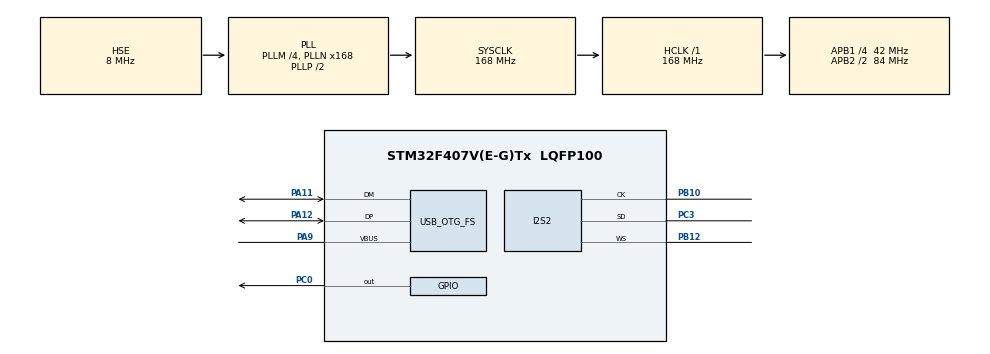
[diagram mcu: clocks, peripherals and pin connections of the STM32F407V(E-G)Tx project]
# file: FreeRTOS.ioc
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Dma.Request0=SPI2_RX
Dma.SPI2_RX.0.Direction=DMA_PERIPH_TO_MEMORY
Dma.SPI2_RX.0.FIFOMode=DMA_FIFOMODE_DISABLE
Dma.SPI2_RX.0.Instance=DMA1_Stream3
Dma.SPI2_RX.0.MemDataAlignment=DMA_MDATAALIGN_HALFWORD
Dma.SPI2_RX.0.MemInc=DMA_MINC_ENABLE
Dma.SPI2_RX.0.Mode=DMA_CIRCULAR
Dma.SPI2_RX.0.PeriphDataAlignment=DMA_PDATAALIGN_HALFWORD
Dma.SPI2_RX.0.PeriphInc=DMA_PINC_DISABLE
Dma.SPI2_RX.0.Priority=DMA_PRIORITY_LOW
FREERTOS.HEAP_NUMBER=5
FREERTOS.Tasks01=defaultTask,24,1024,StartDefaultTask,Default,NULL,Dynamic,NULL,NULL
FREERTOS.configCHECK_FOR_STACK_OVERFLOW=1
FREERTOS.configMINIMAL_STACK_SIZE=1024
FREERTOS.configTOTAL_HEAP_SIZE=30000
FREERTOS.configUSE_MALLOC_FAILED_HOOK=1
I2S2.AudioFreq=I2S_AUDIOFREQ_16K
I2S2.CPOL=I2S_CPOL_HIGH
I2S2.ErrorAudioFreq=-0.79 %
I2S2.FullDuplexMode=I2S_FULLDUPLEXMODE_DISABLE
I2S2.Instance=SPI$Index
I2S2.Mode=I2S_MODE_MASTER_RX
I2S2.RealAudioFreq=15.873 KHz
I2S2.Standard=I2S_STANDARD_LSB
I2S2.VirtualMode=I2S_MODE_MASTER
Mcu.Family=STM32F4
Mcu.Name=STM32F407V(E-G)Tx
Mcu.Package=LQFP100
NVIC.DMA1_Stream3_IRQn=true\:5\:0\:false\:false\:true\:true\:false\:true
NVIC.OTG_FS_IRQn=true\:5\:0\:false\:false\:true\:true\:false\:true
NVIC.PriorityGroup=NVIC_PRIORITYGROUP_4
NVIC.TIM1_UP_TIM10_IRQn=true\:0\:0\:false\:false\:true\:false\:false\:true
NVIC.TimeBase=TIM1_UP_TIM10_IRQn
NVIC.TimeBaseIP=TIM1
PA11.Mode=Host_Only
PA11.Signal=USB_OTG_FS_DM
PA12.Mode=Host_Only
PA12.Signal=USB_OTG_FS_DP
PA9.Mode=Activate_VBUS
PA9.Signal=USB_OTG_FS_VBUS
PB10.Mode=Half_Duplex_Master
PB10.Signal=I2S2_CK
PB12.Mode=Half_Duplex_Master
PB12.Signal=I2S2_WS
PC0.Signal=GPIO_Output
PC3.Mode=Half_Duplex_Master
PC3.Signal=I2S2_SD
PH0-OSC_IN.Mode=HSE-External-Oscillator
PH0-OSC_IN.Signal=RCC_OSC_IN
PH1-OSC_OUT.Mode=HSE-External-Oscillator
PH1-OSC_OUT.Signal=RCC_OSC_OUT
ProjectManager.HeapSize=0x200
ProjectManager.StackSize=0x400
ProjectManager.TargetToolchain=STM32CubeIDE
RCC.48MHZClocksFreq_Value=48000000
RCC.AHBFreq_Value=168000000
RCC.APB1CLKDivider=RCC_HCLK_DIV4
RCC.APB1Freq_Value=42000000
RCC.APB1TimFreq_Value=84000000
RCC.APB2CLKDivider=RCC_HCLK_DIV2
RCC.APB2Freq_Value=84000000
RCC.APB2TimFreq_Value=168000000
RCC.CortexFreq_Value=168000000
RCC.HCLKFreq_Value=168000000
RCC.HSE_VALUE=8000000
RCC.HSI_VALUE=16000000
RCC.LSE_VALUE=32768
RCC.PLLI2SN=96
RCC.PLLI2SR=6
RCC.PLLM=4
RCC.PLLN=168
RCC.PLLQ=7
RCC.SYSCLKFreq_VALUE=168000000
RCC.SYSCLKSource=RCC_SYSCLKSOURCE_PLLCLK
RCC.VCOOutputFreq_Value=336000000
USB_HOST.BSP.number=1
USB_HOST.USBH_HandleTypeDef-MSC_FS=hUsbHostFS
USB_HOST.VirtualModeFS=Msc
USB_HOST0.BSP.STBoard=false
USB_HOST0.BSP.api=Unknown
USB_HOST0.BSP.i2caddr=0
USB_HOST0.BSP.instance=PC0
USB_HOST0.BSP.ip=GPIO
USB_HOST0.BSP.mode=Output
USB_HOST0.BSP.name=Drive_VBUS_FS
USB_HOST0.BSP.solution=PC0
USB_OTG_FS.VirtualMode=Host_Only
USB_OTG_FS.phy_itface=HCD_PHY_EMBEDDED
VP_FATFS_VS_USB.Mode=USB
VP_FREERTOS_VS_CMSIS_V2.Mode=CMSIS_V2
VP_SYS_VS_tim1.Mode=TIM1
VP_USB_HOST_VS_USB_HOST_MSC_FS.Mode=MSC_FS
board=STM32F4DISCOVERY

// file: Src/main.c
/* USER CODE BEGIN Header */
/**
  ******************************************************************************
  * @file           : main.c
  * @brief          : Main program body
  ******************************************************************************
  * @attention
  *
  * <h2><center>&copy; Copyright (c) 2019 STMicroelectronics.
  * All rights reserved.</center></h2>
  *
  * This software component is licensed by ST under BSD 3-Clause license,
  * the "License"; You may not use this file except in compliance with the
  * License. You may obtain a copy of the License at:
  *                        opensource.org/licenses/BSD-3-Clause
  *
  ******************************************************************************
  */
/* USER CODE END Header */

#include "main.h"
#include "cmsis_os.h"
#include "fatfs.h"
#include "usb_host.h"

/* USER CODE BEGIN Includes */
#include "pdm2pcm_glo.h"
#include "task.h"
/* USER CODE END Includes */

/* USER CODE BEGIN PD */
#if     (malloc == USBH_malloc)
#undef  USBH_malloc
#define USBH_malloc   pvPortMalloc
#endif

#if     (free == USBH_free)
#undef  USBH_free
#define USBH_free   vPortFree
#endif

/* USER CODE END PD */

/* USER CODE BEGIN PM */
#define REC_WAVE_NAME "0:rec.wav"
#define HTONS(A)  ((((uint16_t)(A) & 0xff00) >> 8) | (((uint16_t)(A) & 0x00ff) << 8))
/* USER CODE END PM */

I2S_HandleTypeDef hi2s2;
DMA_HandleTypeDef hdma_spi2_rx;

osThreadId_t defaultTaskHandle;
osThreadId_t Led_task_handle;
/* USER CODE BEGIN PV */
extern ApplicationTypeDef Appli_state;

/* Temporary data sample */
__IO uint32_t AUDIODataReady = 0, AUDIOBuffOffset = 0;

#define FREQ          16000
#define NBR_CHANNELS  2
#define PDM_BUFFER    128
#define PCM_BUFFER    FREQ/1000 * NBR_CHANNELS
#define RC_BUFFER     4096

uint16_t PDM_buffer[PDM_BUFFER];
uint16_t PCM_buffer[PCM_BUFFER];
uint16_t Rc_Buffer[RC_BUFFER];
uint32_t byteswritten = 0;

/* PDM filters params */
PDM_Filter_Handler_t  PDM_FilterHandler[2];
PDM_Filter_Config_t   PDM_FilterConfig[2];

/* Private typedef -----------------------------------------------------------*/
typedef struct {
  int32_t offset;
  uint32_t fptr;
}Audio_BufferTypeDef;

Audio_BufferTypeDef  BufferCtl;
volatile uint16_t ITcounter = 0;

FATFS USBDISKFatFs;          /* File system object for USB disk logical drive */
char USBDISKPath[4];         /* USB Host logical drive path */
uint8_t pHeaderBuff[44];
FIL WavFile;

/* USER CODE END PV */

void SystemClock_Config(void);
static void MX_GPIO_Init(void);
static void MX_DMA_Init(void);
static void MX_I2S2_Init(void);
void StartDefaultTask(void *argument);

/* USER CODE BEGIN PFP */
void Led_commandes(void *argument);
/* USER CODE END PFP */

/* USER CODE BEGIN 0 */

typedef struct
{
  uint32_t   ChunkID;       /* 0 */
  uint32_t   FileSize;      /* 4 */
  uint32_t   FileFormat;    /* 8 */
  uint32_t   SubChunk1ID;   /* 12 */
  uint32_t   SubChunk1Size; /* 16*/
  uint16_t   AudioFormat;   /* 20 */
  uint16_t   NbrChannels;   /* 22 */
  uint32_t   SampleRate;    /* 24 */

  uint32_t   ByteRate;      /* 28 */
  uint16_t   BlockAlign;    /* 32 */
  uint16_t   BitPerSample;  /* 34 */
  uint32_t   SubChunk2ID;   /* 36 */
  uint32_t   SubChunk2Size; /* 40 */

}WAVE_FormatTypeDef;

WAVE_FormatTypeDef WaveFormat;

/**
  * @brief  Initialize the wave header file
  * @param  pHeader: Header Buffer to be filled
  * @param  pWaveFormatStruct: Pointer to the wave structure to be filled.
  * @retval 0 if passed, !0 if failed.
  */
uint32_t WavProcess_HeaderUpdate(uint8_t* pHeader, WAVE_FormatTypeDef* pWaveFormatStruct)
{
  /* Write the file length ----------------------------------------------------*/
  /* The sampling time: this value will be be written back at the end of the
     recording opearation.  Example: 661500 Btyes = 0x000A17FC, byte[7]=0x00, byte[4]=0xFC */
  pHeader[4] = (uint8_t)(BufferCtl.fptr);
  pHeader[5] = (uint8_t)(BufferCtl.fptr >> 8);
  pHeader[6] = (uint8_t)(BufferCtl.fptr >> 16);
  pHeader[7] = (uint8_t)(BufferCtl.fptr >> 24);
  /* Write the number of sample data -----------------------------------------*/
  /* This variable will be written back at the end of the recording operation */
  BufferCtl.fptr -=44;
  pHeader[40] = (uint8_t)(BufferCtl.fptr);
  pHeader[41] = (uint8_t)(BufferCtl.fptr >> 8);
  pHeader[42] = (uint8_t)(BufferCtl.fptr >> 16);
  pHeader[43] = (uint8_t)(BufferCtl.fptr >> 24);
  /* Return 0 if all operations are OK */
  return 0;
}
/**
  * @brief  Initialize the wave header file
  * @param  pHeader: Header Buffer to be filled
  * @param  pWaveFormatStruct: Pointer to the wave structure to be filled.
  * @retval 0 if passed, !0 if failed.
  */
uint32_t WavProcess_HeaderInit(uint8_t* pHeader, WAVE_FormatTypeDef* pWaveFormatStruct)
{
  /* Write chunkID, must be 'RIFF'  ------------------------------------------*/
  pHeader[0] = 'R';
  pHeader[1] = 'I';
  pHeader[2] = 'F';
  pHeader[3] = 'F';

  /* Write the file length ----------------------------------------------------*/
  /* The sampling time: this value will be be written back at the end of the
     recording opearation.  Example: 661500 Btyes = 0x000A17FC, byte[7]=0x00, byte[4]=0xFC */
  pHeader[4] = 0x00;
  pHeader[5] = 0x4C;
  pHeader[6] = 0x1D;
  pHeader[7] = 0x00;

  /* Write the file format, must be 'WAVE' -----------------------------------*/
  pHeader[8]  = 'W';
  pHeader[9]  = 'A';
  pHeader[10] = 'V';
  pHeader[11] = 'E';

  /* Write the format chunk, must be'fmt ' -----------------------------------*/
  pHeader[12]  = 'f';
  pHeader[13]  = 'm';
  pHeader[14]  = 't';
  pHeader[15]  = ' ';

  /* Write the length of the 'fmt' data, must be 0x10 ------------------------*/
  pHeader[16]  = 0x10;
  pHeader[17]  = 0x00;
  pHeader[18]  = 0x00;
  pHeader[19]  = 0x00;

  /* Write the audio format, must be 0x01 (PCM) ------------------------------*/
  pHeader[20]  = 0x01;
  pHeader[21]  = 0x00;

  /* Write the number of channels, ie. 0x01 (Mono) ---------------------------*/
  pHeader[22]  = pWaveFormatStruct->NbrChannels;
  pHeader[23]  = 0x00;

  /* Write the Sample Rate in Hz ---------------------------------------------*/
  /* Write Little Endian ie. 8000 = 0x00001F40 => byte[24]=0x40, byte[27]=0x00*/
  pHeader[24]  = (uint8_t)((pWaveFormatStruct->SampleRate & 0xFF));
  pHeader[25]  = (uint8_t)((pWaveFormatStruct->SampleRate >> 8) & 0xFF);
  pHeader[26]  = (uint8_t)((pWaveFormatStruct->SampleRate >> 16) & 0xFF);
  pHeader[27]  = (uint8_t)((pWaveFormatStruct->SampleRate >> 24) & 0xFF);

  /* Write the Byte Rate -----------------------------------------------------*/
  pHeader[28]  = (uint8_t)((pWaveFormatStruct->ByteRate & 0xFF));
  pHeader[29]  = (uint8_t)((pWaveFormatStruct->ByteRate >> 8) & 0xFF);
  pHeader[30]  = (uint8_t)((pWaveFormatStruct->ByteRate >> 16) & 0xFF);
  pHeader[31]  = (uint8_t)((pWaveFormatStruct->ByteRate >> 24) & 0xFF);

  /* Write the block alignment -----------------------------------------------*/
  pHeader[32]  = pWaveFormatStruct->BlockAlign;
  pHeader[33]  = 0x00;

  /* Write the number of bits per sample -------------------------------------*/
  pHeader[34]  = pWaveFormatStruct->BitPerSample;
  pHeader[35]  = 0x00;

  /* Write the Data chunk, must be 'data' ------------------------------------*/
  pHeader[36]  = 'd';
  pHeader[37]  = 'a';
  pHeader[38]  = 't';
  pHeader[39]  = 'a';

  /* Write the number of sample data -----------------------------------------*/
  /* This variable will be written back at the end of the recording operation */
  pHeader[40]  = 0x00;
  pHeader[41]  = 0x4C;
  pHeader[42]  = 0x1D;
  pHeader[43]  = 0x00;

  /* Return 0 if all operations are OK */
  return 0;
}

/**
  * @brief  Encoder initialization.
  * @param  Freq: Sampling frequency.
  * @param  pHeader: Pointer to the WAV file header to be written.
  * @retval 0 if success, !0 else.
  */
uint32_t WavProcess_EncInit(uint32_t Freq, uint8_t* pHeader)
{
  /* Initialize the encoder structure */
  WaveFormat.SampleRate = Freq;        /* Audio sampling frequency */
  WaveFormat.NbrChannels = 2;          /* Number of channels: 1:Mono or 2:Stereo */
  WaveFormat.BitPerSample = 16;        /* Number of bits per sample (16, 24 or 32) */
  WaveFormat.FileSize = 0x001D4C00;    /* Total length of useful audio data (payload) */
  WaveFormat.SubChunk1Size = 44;       /* The file header chunk size */
  WaveFormat.ByteRate = (WaveFormat.SampleRate * \
                        (WaveFormat.BitPerSample/8) * \
                         WaveFormat.NbrChannels);     /* Number of bytes per second  (sample rate * block align)  */
  WaveFormat.BlockAlign = WaveFormat.NbrChannels * \
                         (WaveFormat.BitPerSample/8); /* channels * bits/sample / 8 */

  /* Parse the wav file header and extract required information */
  if(WavProcess_HeaderInit(pHeader, &WaveFormat))
  {
    return 1;
  }
  return 0;
}

/**
  * @brief  Initializes the PDM library.
  * @param  AudioFreq: Audio sampling frequency
  * @param  ChnlNbrIn: Number of input audio channels in the PDM buffer
  * @param  ChnlNbrOut: Number of desired output audio channels in the  resulting PCM buffer
  *         Number of audio channels (1: mono; 2: stereo)
  */
void PDMDecoder_Init(uint32_t AudioFreq, uint32_t ChnlNbrIn, uint32_t ChnlNbrOut)
{
  uint32_t index = 0;

  /* Enable CRC peripheral to unlock the PDM library */
  __HAL_RCC_CRC_CLK_ENABLE();

  for(index = 0; index < ChnlNbrIn; index++)
  {
    /* Init PDM filters */
    PDM_FilterHandler[index].bit_order  = PDM_FILTER_BIT_ORDER_LSB;
    PDM_FilterHandler[index].endianness = PDM_FILTER_ENDIANNESS_LE;
    PDM_FilterHandler[index].high_pass_tap = 2122358088;
    PDM_FilterHandler[index].out_ptr_channels = ChnlNbrOut;
    PDM_FilterHandler[index].in_ptr_channels  = ChnlNbrIn;
    PDM_Filter_Init((PDM_Filter_Handler_t *)(&PDM_FilterHandler[index]));

    /* PDM lib config phase */
    PDM_FilterConfig[index].output_samples_number = AudioFreq/1000;
    PDM_FilterConfig[index].mic_gain = 50;
    PDM_FilterConfig[index].decimation_factor = PDM_FILTER_DEC_FACTOR_64;
    PDM_Filter_setConfig((PDM_Filter_Handler_t *)&PDM_FilterHandler[index], &PDM_FilterConfig[index]);
  }
}
/**
  * @brief  Converts audio format from PDM to PCM.
  * @param  PDMBuf: Pointer to data PDM buffer
  * @param  PCMBuf: Pointer to data PCM buffer
  * @retval AUDIO_OK if correct communication, else wrong communication
  */
uint8_t AUDIO_IN_PDMToPCM(uint16_t *PDMBuf, uint16_t *PCMBuf)
{
  uint16_t AppPDM[64];
  uint32_t index = 0;

  /* PDM Demux */
  for(index = 0; index < 64; index++)
  {
    AppPDM[index] = HTONS(PDMBuf[index]);
  }

  for(index = 0; index < 1; index++)
  {
    /* PDM to PCM filter */
	PDM_Filter((uint8_t*)&AppPDM[index], (uint16_t*)&(PCMBuf[index]), &PDM_FilterHandler[index]);
  }
  /* Duplicate samples since a single microphone in mounted on STM32F4-Discovery */
  for(index = 0; index < 16; index++)
  {
    PCMBuf[(index<<1)+1] = PCMBuf[index<<1];
  }

  /* Return AUDIO_OK when all operations are correctly done */
  return 1;
}
/* USER CODE END 0 */

int main(void)
{

  /* MCU Configuration--------------------------------------------------------*/

  /* Reset of all peripherals, Initializes the Flash interface and the Systick. */
  HAL_Init();

  /* Configure the system clock */
  SystemClock_Config();

  /* Initialize all configured peripherals */
  MX_GPIO_Init();
  MX_DMA_Init();
  MX_I2S2_Init();
  /* USER CODE BEGIN 2 */
    PDMDecoder_Init(FREQ,1,NBR_CHANNELS);
    memset(PDM_buffer,0,sizeof(uint16_t)*128);
    memset(PCM_buffer,0,sizeof(uint16_t)*16);
  /* USER CODE END 2 */

  osKernelInitialize();

  /* Create the thread(s) */
  /* definition and creation of defaultTask */
  const osThreadAttr_t defaultTask_attributes = {
    .name = "defaultTask",
    .priority = (osPriority_t) osPriorityNormal,
    .stack_size = 1024
  };
  defaultTaskHandle = osThreadNew(StartDefaultTask, NULL, &defaultTask_attributes);
  Led_task_handle =  osThreadNew(Led_commandes, NULL, &defaultTask_attributes);

  /* Start scheduler */
  osKernelStart();

  /* We should never get here as control is now taken by the scheduler */

  /* Infinite loop */
  while (1)
  {

  }
}

void SystemClock_Config(void)
{
  RCC_OscInitTypeDef RCC_OscInitStruct = {0};
  RCC_ClkInitTypeDef RCC_ClkInitStruct = {0};
  RCC_PeriphCLKInitTypeDef PeriphClkInitStruct = {0};

  /** Configure the main internal regulator output voltage
  */
  __HAL_RCC_PWR_CLK_ENABLE();
  __HAL_PWR_VOLTAGESCALING_CONFIG(PWR_REGULATOR_VOLTAGE_SCALE1);
  /** Initializes the CPU, AHB and APB busses clocks
  */
  RCC_OscInitStruct.OscillatorType = RCC_OSCILLATORTYPE_HSE;
  RCC_OscInitStruct.HSEState = RCC_HSE_ON;
  RCC_OscInitStruct.PLL.PLLState = RCC_PLL_ON;
  RCC_OscInitStruct.PLL.PLLSource = RCC_PLLSOURCE_HSE;
  RCC_OscInitStruct.PLL.PLLM = 4;
  RCC_OscInitStruct.PLL.PLLN = 168;
  RCC_OscInitStruct.PLL.PLLP = RCC_PLLP_DIV2;
  RCC_OscInitStruct.PLL.PLLQ = 7;
  if (HAL_RCC_OscConfig(&RCC_OscInitStruct) != HAL_OK)
  {
    Error_Handler();
  }
  /** Initializes the CPU, AHB and APB busses clocks
  */
  RCC_ClkInitStruct.ClockType = RCC_CLOCKTYPE_HCLK|RCC_CLOCKTYPE_SYSCLK
                              |RCC_CLOCKTYPE_PCLK1|RCC_CLOCKTYPE_PCLK2;
  RCC_ClkInitStruct.SYSCLKSource = RCC_SYSCLKSOURCE_PLLCLK;
  RCC_ClkInitStruct.AHBCLKDivider = RCC_SYSCLK_DIV1;
  RCC_ClkInitStruct.APB1CLKDivider = RCC_HCLK_DIV4;
  RCC_ClkInitStruct.APB2CLKDivider = RCC_HCLK_DIV2;

  if (HAL_RCC_ClockConfig(&RCC_ClkInitStruct, FLASH_LATENCY_5) != HAL_OK)
  {
    Error_Handler();
  }
  PeriphClkInitStruct.PeriphClockSelection = RCC_PERIPHCLK_I2S;
  PeriphClkInitStruct.PLLI2S.PLLI2SN = 96;
  PeriphClkInitStruct.PLLI2S.PLLI2SR = 6;
  if (HAL_RCCEx_PeriphCLKConfig(&PeriphClkInitStruct) != HAL_OK)
  {
    Error_Handler();
  }
}

static void MX_I2S2_Init(void)
{

  hi2s2.Instance = SPI2;
  hi2s2.Init.Mode = I2S_MODE_MASTER_RX;
  hi2s2.Init.Standard = I2S_STANDARD_LSB;
  hi2s2.Init.DataFormat = I2S_DATAFORMAT_16B;
  hi2s2.Init.MCLKOutput = I2S_MCLKOUTPUT_DISABLE;
  hi2s2.Init.AudioFreq = 2*I2S_AUDIOFREQ_16K;
  hi2s2.Init.CPOL = I2S_CPOL_HIGH;
  hi2s2.Init.ClockSource = I2S_CLOCK_PLL;
  hi2s2.Init.FullDuplexMode = I2S_FULLDUPLEXMODE_DISABLE;
  if (HAL_I2S_Init(&hi2s2) != HAL_OK)
  {
    Error_Handler();
  }

}

static void MX_DMA_Init(void)
{

  /* DMA controller clock enable */
  __HAL_RCC_DMA1_CLK_ENABLE();

  /* DMA interrupt init */
  /* DMA1_Stream3_IRQn interrupt configuration */
  HAL_NVIC_SetPriority(DMA1_Stream3_IRQn, 5, 0);
  HAL_NVIC_EnableIRQ(DMA1_Stream3_IRQn);

}

static void MX_GPIO_Init(void)
{
  GPIO_InitTypeDef GPIO_InitStruct = {0};

  /* GPIO Ports Clock Enable */
  __HAL_RCC_GPIOH_CLK_ENABLE();
  __HAL_RCC_GPIOC_CLK_ENABLE();
  __HAL_RCC_GPIOB_CLK_ENABLE();
  __HAL_RCC_GPIOA_CLK_ENABLE();
  __HAL_RCC_GPIOD_CLK_ENABLE();

  /*Configure GPIO pin Output Level */
  HAL_GPIO_WritePin(GPIOC, GPIO_PIN_0, GPIO_PIN_RESET);

  /*Configure GPIO pin : PC0 */
  GPIO_InitStruct.Pin = GPIO_PIN_0;
  GPIO_InitStruct.Mode = GPIO_MODE_OUTPUT_PP;
  GPIO_InitStruct.Pull = GPIO_NOPULL;
  GPIO_InitStruct.Speed = GPIO_SPEED_FREQ_LOW;
  HAL_GPIO_Init(GPIOC, &GPIO_InitStruct);

  /*Configure GPIO pins : PD12 PD13 PD14 PD15 */
  GPIO_InitStruct.Pin = GPIO_PIN_12|GPIO_PIN_13|GPIO_PIN_14|GPIO_PIN_15;
  GPIO_InitStruct.Mode = GPIO_MODE_OUTPUT_PP;
  GPIO_InitStruct.Pull = GPIO_NOPULL;
  GPIO_InitStruct.Speed = GPIO_SPEED_FREQ_LOW;
  HAL_GPIO_Init(GPIOD, &GPIO_InitStruct);

}

/* USER CODE BEGIN 4 */

void Led_commandes(void *argument)
{
	uint32_t Notification_value = 0x00;

	for(;;)
	{
      xTaskNotifyWait(1, 0, &Notification_value, 1000);
      HAL_GPIO_TogglePin(GPIOD,Notification_value);
	}
}

void USBH_UserProcess  (USBH_HandleTypeDef *phost, uint8_t id)
{
  /* USER CODE BEGIN CALL_BACK_1 */
  switch(id)
  {
  case HOST_USER_SELECT_CONFIGURATION:
  break;

  case HOST_USER_DISCONNECTION:
  Appli_state = APPLICATION_DISCONNECT;
  break;

  case HOST_USER_CLASS_ACTIVE:
	  /* Initializes the File System */
	  if (f_mount(&USBDISKFatFs,(TCHAR const*)USBHPath,0) != FR_OK )
	  {
	    /* FatFs initialisation fails */
	    Error_Handler();
	  }

	  /* Remove Wave file if it exists on USB Flash Disk */
	  f_unlink (REC_WAVE_NAME);

	  if ((f_open(&WavFile, REC_WAVE_NAME, FA_CREATE_ALWAYS | FA_WRITE) != FR_OK))
	  {
	    while(1)
	    {
	      /* Toggle LED5 in infinite loop to signal that: USB Flash Disk is not connected/removed
	         or an issue has occurred when creating/opening Wave file */
	    }
	  }
	  /* Initialize header file */
	  WavProcess_EncInit(16000, pHeaderBuff);
	  /* Write the header Wave */
	  f_write(&WavFile, pHeaderBuff, 44, (void *)&byteswritten);

	  /* Increment the Wave counter */
	  BufferCtl.fptr = byteswritten;
	  HAL_I2S_Receive_DMA(&hi2s2, PDM_buffer, PDM_BUFFER);
      //envoi de notification pour la tache qui gere les leds
	  if( xTaskNotify( Led_task_handle, GPIO_PIN_13, eSetValueWithOverwrite ) == pdPASS )
	  {
		 /* The task's notification value was updated. */
	  }
	  else
	  {
		 /* The task's notification value was not updated. */
	  }
	  ITcounter = 0;
  Appli_state = APPLICATION_READY;
  break;

  case HOST_USER_CONNECTION:
  Appli_state = APPLICATION_START;
  break;

  default:
  break;
  }
  /* USER CODE END CALL_BACK_1 */
}

/**
  * @brief  Rx Transfer half completed callbacks
  * @param  hi2s pointer to a I2S_HandleTypeDef structure that contains
  *         the configuration information for I2S module
  * @retval None
  */
void HAL_I2S_RxHalfCpltCallback(I2S_HandleTypeDef *hi2s)
{
  /* Prevent unused argument(s) compilation warning */
  UNUSED(hi2s);
  AUDIO_IN_PDMToPCM((uint16_t*)&PDM_buffer[0], (uint16_t*)&PCM_buffer[0]);
  memcpy((uint16_t*)&Rc_Buffer[32*ITcounter],(uint8_t*)PCM_buffer,64);

  if(ITcounter == (RC_BUFFER/(2*(PCM_BUFFER)))-1)
  {
    AUDIODataReady = 1;
    AUDIOBuffOffset = 0;
    ITcounter++;
  }
  else if(ITcounter == (RC_BUFFER/(PCM_BUFFER))-1)
  {
    AUDIODataReady = 1;
    AUDIOBuffOffset = 2048;
    ITcounter = 0;
  }
  else
  {
	  ITcounter++;
  }
  //f_write(&WavFile,(uint8_t*) PCM_buffer,64, (void*)&byteswritten);
  //BufferCtl.fptr += 64;
  /* NOTE : This function Should not be modified, when the callback is needed,
            the HAL_I2S_RxHalfCpltCallback could be implemented in the user file
   */
}

/**
  * @brief  Rx Transfer completed callbacks
  * @param  hi2s pointer to a I2S_HandleTypeDef structure that contains
  *         the configuration information for I2S module
  * @retval None
  */
void HAL_I2S_RxCpltCallback(I2S_HandleTypeDef *hi2s)
{
  /* Prevent unused argument(s) compilation warning */
  UNUSED(hi2s);
  AUDIO_IN_PDMToPCM((uint16_t*)&PDM_buffer[64], (uint16_t*)&PCM_buffer[0]);
  memcpy((uint16_t*)&Rc_Buffer[32*ITcounter],(uint8_t*)PCM_buffer,64);
  if(ITcounter == (RC_BUFFER/(2*(PCM_BUFFER)))-1)
  {
    AUDIODataReady = 1;
    AUDIOBuffOffset = 0;
    ITcounter++;
  }
  else if(ITcounter == (RC_BUFFER/(PCM_BUFFER))-1)
  {
    AUDIODataReady = 1;
    AUDIOBuffOffset = 2048;
    ITcounter = 0;
  }
  else
  {
	  ITcounter++;
  }
  /* NOTE : This function Should not be modified, when the callback is needed,
            the HAL_I2S_RxCpltCallback could be implemented in the user file
   */
}

/* USER CODE END 4 */

void StartDefaultTask(void *argument)
{

  /* init code for USB_HOST */
  MX_USB_HOST_Init();

  /* init code for FATFS */
  MX_FATFS_Init();

  /* USER CODE BEGIN 5 */
  /* Infinite loop */
  for(;;)
  {
	 if(  Appli_state == APPLICATION_READY)
	 {
		 /* Check if there are Data to write in Usb Key */
	   if(AUDIODataReady == 1)
	   {
		 /* write buffer in file */
		 if(f_write(&WavFile, (uint8_t*)(Rc_Buffer+AUDIOBuffOffset), RC_BUFFER, (void*)&byteswritten) != 0)
		 {
		   Error_Handler();
		 }
		 BufferCtl.fptr += byteswritten;
		 AUDIODataReady = 0;
	   }
	   if(BufferCtl.fptr  > 200000000)
	   {
		   HAL_I2S_DMAStop(&hi2s2);
		  /* Update the data length in the header of the recorded Wave */
		  f_lseek(&WavFile, 0);
		  HAL_GPIO_WritePin(GPIOD, GPIO_PIN_12, GPIO_PIN_SET);
		  /* Parse the wav file header and extract required information */
		  WavProcess_HeaderUpdate(pHeaderBuff, &WaveFormat);
		  f_write(&WavFile, pHeaderBuff, 44, (void*)&byteswritten);

		  /* Close file and unmount MyFilesystem */
		  f_close (&WavFile);
		  f_mount(NULL, 0, 1);
		  BufferCtl.fptr = 0;
		  //send notification to led task
		  if( xTaskNotify( Led_task_handle, GPIO_PIN_12, eSetValueWithOverwrite ) == pdPASS )
		  {
			 /* The task's notification value was updated. */
		  }
		  else
		  {
			 /* The task's notification value was not updated. */
		  }
	   }
	 }
    //osDelay(1);
  }
  /* USER CODE END 5 */
}

void HAL_TIM_PeriodElapsedCallback(TIM_HandleTypeDef *htim)
{
  if (htim->Instance == TIM1) {
    HAL_IncTick();
  }
}

void Error_Handler(void)
{
}

/************************ (C) COPYRIGHT STMicroelectronics *****END OF FILE****/

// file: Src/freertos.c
/* USER CODE BEGIN Header */
/**
  ******************************************************************************
  * File Name          : freertos.c
  * Description        : Code for freertos applications
  ******************************************************************************
  * @attention
  *
  * <h2><center>&copy; Copyright (c) 2019 STMicroelectronics.
  * All rights reserved.</center></h2>
  *
  * This software component is licensed by ST under Ultimate Liberty license
  * SLA0044, the "License"; You may not use this file except in compliance with
  * the License. You may obtain a copy of the License at:
  *                             www.st.com/SLA0044
  *
  ******************************************************************************
  */
/* USER CODE END Header */

#include "FreeRTOS.h"
#include "task.h"
#include "main.h"

/* Hook prototypes */
void vApplicationStackOverflowHook(xTaskHandle xTask, signed char *pcTaskName);
void vApplicationMallocFailedHook(void);

/* USER CODE BEGIN 4 */
__weak void vApplicationStackOverflowHook(xTaskHandle xTask, signed char *pcTaskName)
{
   /* Run time stack overflow checking is performed if
   configCHECK_FOR_STACK_OVERFLOW is defined to 1 or 2. This hook function is
   called if a stack overflow is detected. */
}
/* USER CODE END 4 */

/* USER CODE BEGIN 5 */
__weak void vApplicationMallocFailedHook(void)
{
   /* vApplicationMallocFailedHook() will only be called if
   configUSE_MALLOC_FAILED_HOOK is set to 1 in FreeRTOSConfig.h. It is a hook
   function that will get called if a call to pvPortMalloc() fails.
   pvPortMalloc() is called internally by the kernel whenever a task, queue,
   timer or semaphore is created. It is also called by various parts of the
   demo application. If heap_1.c or heap_2.c are used, then the size of the
   heap available to pvPortMalloc() is defined by configTOTAL_HEAP_SIZE in
   FreeRTOSConfig.h, and the xPortGetFreeHeapSize() API function can be used
   to query the size of free heap space that remains (although it does not
   provide information on how the remaining heap might be fragmented). */
}
/* USER CODE END 5 */

/************************ (C) COPYRIGHT STMicroelectronics *****END OF FILE****/
